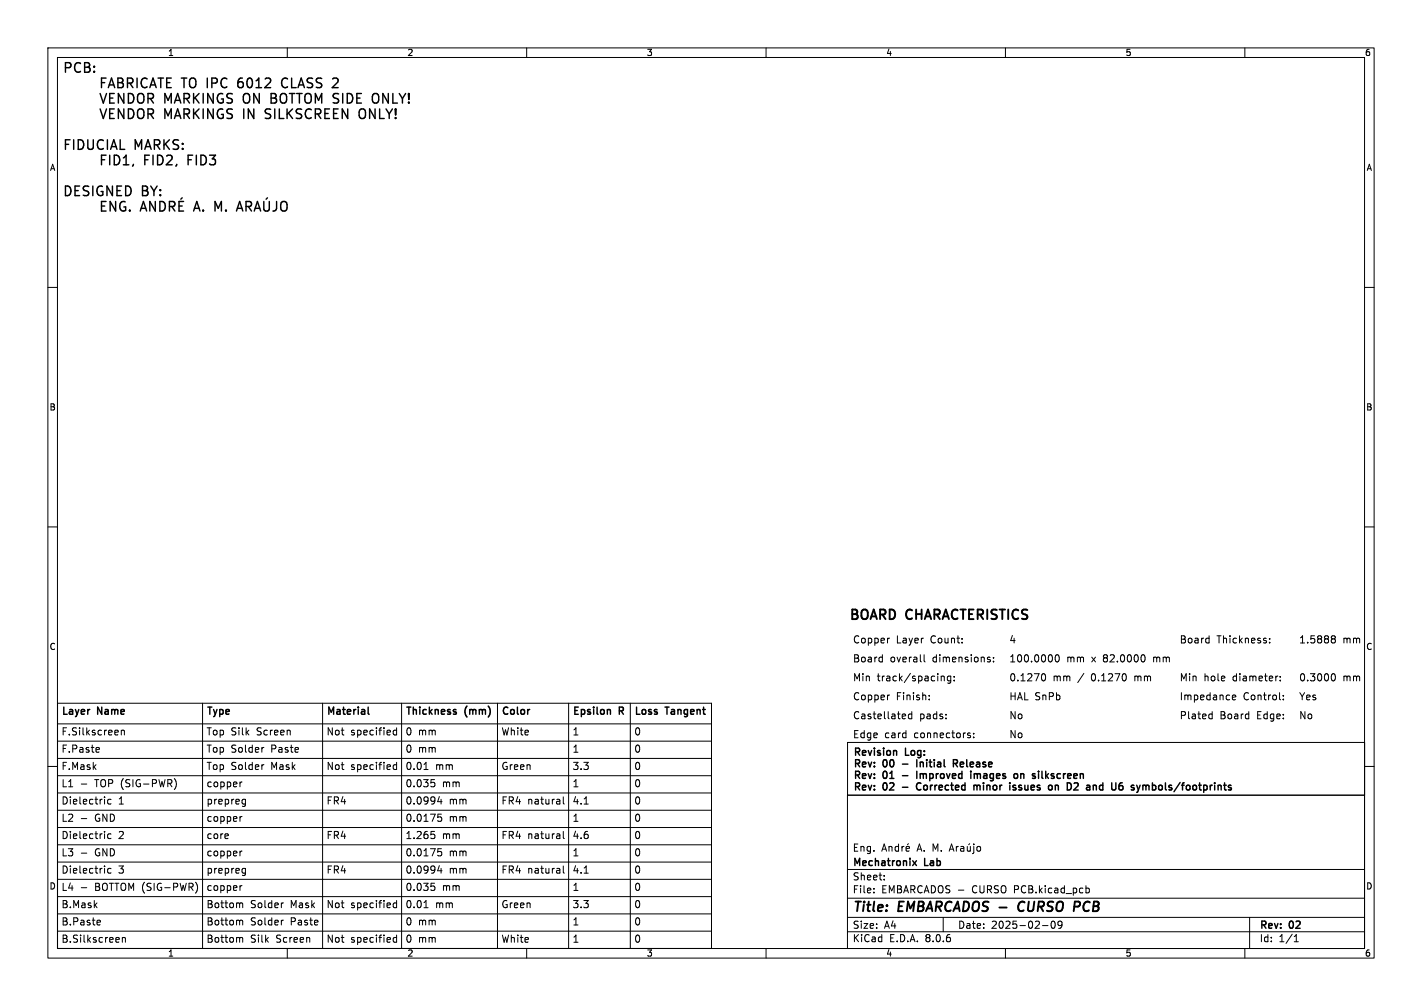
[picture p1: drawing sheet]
<svg xmlns="http://www.w3.org/2000/svg" width="297mm" height="210mm" viewBox="0 0 297 210" stroke-linecap="round" stroke-linejoin="round" font-family="sans-serif">
<defs><g id="words">
<g font-size="2.8">
<text x="13" y="15.9">PCB:</text>
<text x="13" y="19.1">FABRICATE</text>
<text x="13" y="22.3">VENDOR</text>
<text x="34.3" y="22.3">MARKINGS</text>
<text x="38" y="19.1">TO IPC</text>
<text x="50.6" y="19.1">6012</text>
<text x="51.2" y="22.3">ON</text>
<text x="57.5" y="22.3">BOTTOM SIDE</text>
<text x="60.2" y="19.1">CLASS</text>
<text x="71.4" y="19.1">2</text>
<text x="79.7" y="22.3">ONLY!</text>
<text x="13" y="25.6">VENDOR</text>
<text x="34.3" y="25.6">MARKINGS</text>
<text x="51.2" y="25.6">IN</text>
<text x="56.3" y="25.6">SILKSCREEN</text>
<text x="76.4" y="25.6">ONLY!</text>
<text x="13" y="32">FIDUCIAL</text>
<text x="28.1" y="32">MARKS:</text>
<text x="30.1" y="35.2">FID2,</text>
<text x="39.6" y="35.2">FID3</text>
<text x="13" y="41.7">DESIGNED</text>
<text x="29.6" y="41.7">BY:</text>
<text x="41" y="44.9">A.</text>
<text x="177.3" y="130.4">BOARD</text>
<text x="189.4" y="130.4">CHARACTERISTICS</text>
<text x="178" y="190.9">Title:</text>
<text x="187.7" y="190.9">EMBARCADOS -</text>
<text x="214.3" y="190.9">CURSO</text>
<text x="226.7" y="190.9">PCB</text>
</g>
<g font-size="2.1">
<text x="178" y="134.8">Copper</text>
<text x="187.2" y="134.8">Layer</text>
<text x="194.6" y="134.8">Count:</text>
<text x="210.7" y="134.8">4</text>
<text x="246.3" y="134.8">Board</text>
<text x="254.2" y="134.8">Thickness:</text>
<text x="271.2" y="134.8">1.5888</text>
<text x="280.5" y="134.8">mm</text>
<text x="178" y="142.7">Min</text>
<text x="178" y="138.7">Board</text>
<text x="183.2" y="142.7">track/spacing:</text>
<text x="186" y="138.7">overall</text>
<text x="195" y="138.7">dimensions:</text>
<text x="210.7" y="142.7">0.1270</text>
<text x="210.7" y="138.7">100.0000</text>
<text x="220" y="142.7">mm</text>
<text x="222.8" y="138.7">mm</text>
<text x="225.4" y="142.7">/</text>
<text x="228.3" y="138.7">x</text>
<text x="228.4" y="142.7">0.1270</text>
<text x="230.9" y="138.7">82.0000</text>
<text x="237.7" y="142.7">mm</text>
<text x="241.7" y="138.7">mm</text>
<text x="246.3" y="142.7">Min</text>
<text x="251.5" y="142.7">hole</text>
<text x="257.7" y="142.7">diameter:</text>
<text x="271.2" y="142.7">0.3000</text>
<text x="280.5" y="142.7">mm</text>
<text x="12.8" y="150">Layer</text>
<text x="20.4" y="150">Name</text>
<text x="43.1" y="150">Type</text>
<text x="68.1" y="150">Material</text>
<text x="84.6" y="150">Thickness</text>
<text x="97.2" y="150">(mm)</text>
<text x="104.7" y="150">Color</text>
<text x="119.5" y="150">Epsilon</text>
<text x="129.4" y="150">R</text>
<text x="132.4" y="150">Loss</text>
<text x="139.1" y="150">Tangent</text>
<text x="178" y="146.6">Copper</text>
<text x="187.2" y="146.6">Finish:</text>
<text x="210.7" y="146.6">HAL SnPb</text>
<text x="246.3" y="146.6">Impedance</text>
<text x="259.7" y="146.6">Control:</text>
<text x="271.2" y="146.6">Yes</text>
<text x="12.8" y="153.7">F.Silkscreen</text>
<text x="43.1" y="153.7">Top Silk</text>
<text x="53.3" y="153.7">Screen</text>
<text x="68.1" y="153.7">Not</text>
<text x="73.1" y="153.7">specified</text>
<text x="84.6" y="153.7">0 mm</text>
<text x="104.7" y="153.7">White</text>
<text x="119.5" y="153.7">1</text>
<text x="132.4" y="153.7">0</text>
<text x="178" y="154.5">Edge</text>
<text x="178" y="150.6">Castellated</text>
<text x="184.8" y="154.5">card</text>
<text x="191.2" y="154.5">connectors:</text>
<text x="192.1" y="150.6">pads:</text>
<text x="210.7" y="150.6">No</text>
<text x="210.7" y="154.5">No</text>
<text x="246.3" y="150.6">Plated</text>
<text x="254.8" y="150.6">Board</text>
<text x="262.8" y="150.6">Edge:</text>
<text x="271.2" y="150.6">No</text>
<text x="12.8" y="157.3">F.Paste</text>
<text x="12.8" y="160.9">F.Mask</text>
<text x="43.1" y="157.3">Top Solder</text>
<text x="43.1" y="160.9">Top Solder</text>
<text x="56.3" y="157.3">Paste</text>
<text x="56.3" y="160.9">Mask</text>
<text x="68.1" y="160.9">Not</text>
<text x="73.1" y="160.9">specified</text>
<text x="84.6" y="160.9">0.01</text>
<text x="84.6" y="157.3">0 mm</text>
<text x="90.8" y="160.9">mm</text>
<text x="104.7" y="160.9">Green</text>
<text x="119.5" y="157.3">1</text>
<text x="119.5" y="160.9">3.3</text>
<text x="132.4" y="160.9">0</text>
<text x="132.4" y="157.3">0</text>
<text x="178.1" y="158.5">Revision</text>
<text x="178.1" y="160.9">Rev:</text>
<text x="184.5" y="160.9">00</text>
<text x="189.2" y="158.5">Log:</text>
<text x="192.7" y="160.9">Initial</text>
<text x="201" y="160.9">Release</text>
<text x="12.8" y="164.5">L1</text>
<text x="19.6" y="164.5">TOP (SIG-PWR)</text>
<text x="43.1" y="164.5">copper</text>
<text x="84.6" y="164.5">0.035</text>
<text x="92.2" y="164.5">mm</text>
<text x="119.5" y="164.5">1</text>
<text x="132.4" y="164.5">0</text>
<text x="178.1" y="163.3">Rev:</text>
<text x="178.1" y="165.8">Rev:</text>
<text x="184.5" y="163.3">01</text>
<text x="184.5" y="165.8">02</text>
<text x="192.7" y="163.3">Improved</text>
<text x="192.7" y="165.8">Corrected</text>
<text x="204.6" y="163.3">images</text>
<text x="205.3" y="165.8">minor</text>
<text x="213.4" y="165.8">issues</text>
<text x="214.3" y="163.3">on</text>
<text x="218.7" y="163.3">silkscreen</text>
<text x="222.1" y="165.8">on</text>
<text x="226.6" y="165.8">D2</text>
<text x="231.2" y="165.8">and</text>
<text x="237" y="165.8">U6</text>
<text x="241.8" y="165.8">symbols/footprints</text>
<text x="12.8" y="168.1">Dielectric</text>
<text x="12.8" y="171.7">L2</text>
<text x="19.6" y="171.7">GND</text>
<text x="24.6" y="168.1">1</text>
<text x="43.1" y="168.1">prepreg</text>
<text x="43.1" y="171.7">copper</text>
<text x="68.1" y="168.1">FR4</text>
<text x="84.6" y="168.1">0.0994</text>
<text x="84.6" y="171.7">0.0175</text>
<text x="93.6" y="168.1">mm</text>
<text x="93.6" y="171.7">mm</text>
<text x="104.7" y="168.1">FR4 natural</text>
<text x="119.5" y="168.1">4.1</text>
<text x="119.5" y="171.7">1</text>
<text x="132.4" y="168.1">0</text>
<text x="132.4" y="171.7">0</text>
<text x="12.8" y="178.9">L3</text>
<text x="12.8" y="175.3">Dielectric</text>
<text x="19.6" y="178.9">GND</text>
<text x="24.6" y="175.3">2</text>
<text x="43.1" y="178.9">copper</text>
<text x="43.1" y="175.3">core</text>
<text x="68.1" y="175.3">FR4</text>
<text x="84.6" y="178.9">0.0175</text>
<text x="84.6" y="175.3">1.265</text>
<text x="92.2" y="175.3">mm</text>
<text x="93.6" y="178.9">mm</text>
<text x="104.7" y="175.3">FR4 natural</text>
<text x="119.5" y="175.3">4.6</text>
<text x="119.5" y="178.9">1</text>
<text x="132.4" y="175.3">0</text>
<text x="132.4" y="178.9">0</text>
<text x="178" y="178">Eng.</text>
<text x="191.6" y="178">A.</text>
<text x="12.8" y="182.5">Dielectric</text>
<text x="24.6" y="182.5">3</text>
<text x="43.1" y="182.5">prepreg</text>
<text x="68.1" y="182.5">FR4</text>
<text x="84.6" y="182.5">0.0994</text>
<text x="93.6" y="182.5">mm</text>
<text x="104.7" y="182.5">FR4 natural</text>
<text x="119.5" y="182.5">4.1</text>
<text x="132.4" y="182.5">0</text>
<text x="178" y="184">Sheet:</text>
<text x="178" y="181.2">Mechatronix</text>
<text x="193.2" y="181.2">Lab</text>
<text x="12.8" y="186.1">L4</text>
<text x="12.8" y="189.7">B.Mask</text>
<text x="19.6" y="186.1">BOTTOM (SIG-PWR)</text>
<text x="43.1" y="189.7">Bottom</text>
<text x="43.1" y="186.1">copper</text>
<text x="52.1" y="189.7">Solder</text>
<text x="60.4" y="189.7">Mask</text>
<text x="68.1" y="189.7">Not</text>
<text x="73.1" y="189.7">specified</text>
<text x="84.6" y="189.7">0.01</text>
<text x="84.6" y="186.1">0.035</text>
<text x="90.8" y="189.7">mm</text>
<text x="92.2" y="186.1">mm</text>
<text x="104.7" y="189.7">Green</text>
<text x="119.5" y="186.1">1</text>
<text x="119.5" y="189.7">3.3</text>
<text x="132.4" y="186.1">0</text>
<text x="132.4" y="189.7">0</text>
<text x="178" y="186.7">File:</text>
<text x="184.1" y="186.7">EMBARCADOS -</text>
<text x="203.2" y="186.7">CURSO PCB.kicad_pcb</text>
<text x="12.8" y="193.3">B.Paste</text>
<text x="12.8" y="196.9">B.Silkscreen</text>
<text x="43.1" y="196.9">Bottom</text>
<text x="43.1" y="193.3">Bottom</text>
<text x="52.1" y="196.9">Silk</text>
<text x="52.1" y="193.3">Solder</text>
<text x="57.4" y="196.9">Screen</text>
<text x="60.4" y="193.3">Paste</text>
<text x="68.1" y="196.9">Not</text>
<text x="73.1" y="196.9">specified</text>
<text x="84.6" y="196.9">0 mm</text>
<text x="84.6" y="193.3">0 mm</text>
<text x="104.7" y="196.9">White</text>
<text x="119.5" y="196.9">1</text>
<text x="119.5" y="193.3">1</text>
<text x="132.4" y="196.9">0</text>
<text x="132.4" y="193.3">0</text>
<text x="178" y="196.9">KiCad</text>
<text x="178" y="194.1">Size:</text>
<text x="184.7" y="194.1">A4</text>
<text x="185.7" y="196.9">E.D.A.</text>
<text x="193.3" y="196.9">8.0.6</text>
<text x="200" y="194.1">Date:</text>
<text x="207" y="194.1">2025-02-09</text>
<text x="263" y="194.3">Rev:</text>
<text x="263" y="196.9">Id:</text>
<text x="267.1" y="196.9">1/1</text>
<text x="269.4" y="194.3">02</text>
</g>
<g font-size="1.8">
<text x="35" y="11.9">1</text>
<text x="85" y="11.9">2</text>
<text x="135" y="11.9">3</text>
<text x="185" y="11.9">4</text>
<text x="235" y="11.9">5</text>
<text x="285" y="11.9">6</text>
<text x="10.3" y="35.9">A</text>
<text x="285.4" y="35.9">A</text>
<text x="10.3" y="85.9">B</text>
<text x="285.3" y="85.9">B</text>
<text x="10.3" y="135.9">C</text>
<text x="285.3" y="135.9">C</text>
<text x="10.3" y="185.9">D</text>
<text x="285.3" y="185.9">D</text>
<text x="35" y="199.9">1</text>
<text x="85" y="199.9">2</text>
<text x="135" y="199.9">3</text>
<text x="185" y="199.9">4</text>
<text x="235" y="199.9">5</text>
<text x="285" y="199.9">6</text>
</g>
</g></defs>
<g fill="none" stroke="#000" stroke-width=".21">
<path d="M10 10h277v190h-277zM12 12h273v186h-273zM60 10v2M110 10v2M160 10v2M210 10v2M260 10v2M10 60h2M285 60h2M10 110h2M285 110h2M184.2 137.2l.1 .1"/>
<path d="M184.3 136.7v1.5M184.3 138.1l-.1 .1M185.8 133.2l-.3 .1M193 136.7v1.3l.2 .2M206.7 137.7l.2 .2-.2 .3M206.7 137.2l.1 .1M207.5 138v.2M207.5 137.3v.1M220.5 136.8l.2-.1a.8 .8 0 0 1 .6 .7 .8 .8 0 0 1-.6 .8l-.2-.2-.1-.4zM239.1 137v.9M241 137.2v1M241.2 137.2l-.2 .1"/>
<path d="M252.4 133.2l.1 .1M252.5 132.7v1.5M252.5 134.2h-.1M265.2 134.1v.1M265.2 133.3v.1M278.2 132.8l.4-.1 .2 .2 .1 .2-.3 .3M278.2 133.3l.1 .1M278.3 133.4h.3M278.3 133.4h-.1M278.6 133.4l.3 .3-.1 .4-.2 .1h-.4M10 160h2M12 146.8h136.6v51.2h-136.6z"/>
<path d="M12 158.3h136.6M12 151.1h136.6M12 154.7h136.6M20.6 156l.2 .4-.7 .1M20.7 157h-.1M25.3 152.4v1M25.3 152.6l.3-.2 .3 .1 .1 .9M42.3 146.8v51.2M55.1 156l-.3 .2M55.1 159.6l-.3 .2M60.6 152.5v.9M62.3 156.1v.3l-.7 .1"/>
<path d="M67.4 146.8v51.2M82.8 151.9v1.5M82.8 159.1v1.5M82.8 152.5l-.4-.1-.3 .3 .2 .7h.5M82.8 159.7l-.4-.1-.3 .3 .2 .7h.5M83.9 146.8v51.2M103.9 146.8v51.2M118.8 146.8v51.2M131.6 146.8v51.2M177 155h108v11h-108zM185.8 145.1l-.3 .1M189.1 149.1l.1 .3-.8 .2"/>
<path d="M190.4 148.6v1.5M190.4 149.1h-.4l-.3 .2 .2 .7h.5M194.1 146v.1M194.1 145.2v.1M196.7 141.2h.5v.9M198.6 141.2l-.4-.1-.3 .3 .1 .7h.6M198.6 141.1v1.3l-.3 .2h-.4M199.3 142v.1M199.3 141.2v.2M202.5 153.5l.2 .2-.2 .3M202.5 153l.2 .1M203.4 153.1v.1"/>
<path d="M203.4 153.9v.1M217.7 140.8l.2-.2a.8 .8 0 0 1 .5 .8 .8 .8 0 0 1-.5 .7l-.2-.1M237 141.1v1M237.2 141.1l-.2 .2M252.8 149.1h.4M253.2 150l-.4 .1M253.2 148.6v1.5M257.4 145.6l.7-.1-.1-.3-.4-.1-.2 .2 .1 .7h.5M267.4 142v.1M267.4 141.2v.2M268 146v.1M268 145.2v.1"/>
<path d="M278.2 140.8l.2-.2a.8 .8 0 0 1 .5 .8 .8 .8 0 0 1-.5 .7l-.2-.1M285 160h2M12 172.7h136.6M12 176.4h136.6M12 169.1h136.6M12 165.5h136.6M12 180h136.6M12 161.9h136.6M17 178.1h1.1M17 170.9h1.1M17 163.7h1.1M23.2 166.9h-.4l-.3 .2 .1 .7h.6"/>
<path d="M23.2 174.1h-.4l-.3 .3 .1 .6h.6M36.4 162.5a1.72 1.72 0 0 1 0 2.3M50.6 177.7l-.5 .3M50.6 170.5l-.5 .2M50.6 163.2l-.5 .3M50.8 166.9h.5M51.3 166.9v1.2l-.2 .2-.3 .1M51.3 167.8l-.5 .1M88.5 160.6h.9M90.1 162.7h.7M90.1 173.6h.7M90.2 163.3h.3l.3 .3v.5l-.6 .1"/>
<path d="M90.2 174.1h.3l.3 .3v.5l-.6 .2M91.5 170h.7M91.5 177.2h.7M91.6 170.5h.4l.3 .3-.2 .6-.5 .1M91.6 177.7h.4l.3 .3-.2 .6-.5 .1M91.8 166.3l-.4 1.1h.9M92.1 166.9v1M117.7 166.4v1.2l.2 .3M117.7 173.6v1.3l.2 .2M122 167.9h.9M177 166h108v32h-108zM184.2 177.7l.5-1.5 .5 1.5"/>
<path d="M184.3 177.3h.7M185.7 176.7v1M185.7 176.8l.2-.1 .3 .1 .1 .9M187.7 176.8l-.5-.1-.2 .3 .1 .6h.6M187.7 176.2v1.5M188.4 176.7v1M188.8 176.7l-.4 .3M189.2 177.2l.8-.1-.1-.3-.4-.1-.3 .2 .1 .7h.6M189.7 176.1l-.2 .2M194.9 177.7v-1.5l.5 1.1 .5-1.1v1.5M196.6 177.6v.1M198.2 177.7l.5-1.5 .5 1.5"/>
<path d="M198.4 177.3h.7M199.7 176.7v1M200.2 176.7l-.5 .3M200.7 176.8h.5l.1 .9M201.3 177.1h-.5l-.2 .2 .2 .4 .5-.1M202 176.7l.1 .9 .4 .1 .2-.1M202.5 176.1l-.2 .2M202.7 176.7v1M203.4 176.2v.1M203.4 176.7v1.3l-.3 .2M204.2 176.8l.3-.1 .3 .3v.4l-.3 .3-.3-.1-.2-.2zM12 190.8h136.6"/>
<path d="M12 183.6h136.6M12 187.2h136.6M12 194.4h136.6M17 185.3h1.1M20.5 192.1l.4 .1 .1 .3-.7 .1M20.9 193l-.4 .1M23.2 181.3h-.4l-.3 .3 .1 .6h.6M25.6 195.8l.2-.1 .3 .1 .1 .9M25.6 195.7v1M40.8 184.2a1.72 1.72 0 0 1 0 2.3M50.3 188.5l.4 .2v.8M50.3 195.7l.4 .2v.8"/>
<path d="M50.3 192.1l.4 .2v.8M50.6 184.9l-.5 .3M50.8 181.3h.5M51.3 181.3v1.2l-.2 .2-.3 .1M51.3 182.2l-.5 .1M59.2 188.5l-.4 .1M59.2 192.1l-.4 .1M60 198v2M64.6 195.8l.1 .9M66.3 192.2l.1 .3-.7 .1M82.8 188v1.5M82.8 195.2v1.5"/>
<path d="M82.8 188.6l-.4-.1-.3 .3 .2 .6h.5M82.8 195.8l-.4-.1-.3 .3 .2 .6h.5M88.5 189.5h.9M90.1 184.4h.7M90.2 185h.3l.3 .2-.1 .6-.5 .1M91.8 180.7l-.4 1.1h.9M92.1 181.3v1M110 198v2M117.7 180.8v1.3l.2 .2M122 182.3h.9M160 198v2M177 194.5h108"/>
<path d="M177 191.5h108M177 187.5h108M177 181.5h108M182.5 186.3v.1M182.5 185.5v.1M184.7 183.6v.1M184.7 182.8v.1M197 191.5v3M210 198v2M217.7 193.2h1.2M219.7 192.4l.2-.1a.8 .8 0 0 1 .5 .7 .8 .8 0 0 1-.5 .8 1 1 0 0 1-.2-1.4zM221.8 192.9l-.3 .3h-.3l-.2-.3 .1-.5 .4-.1 .2 .1a.99 .99 0 0 1-.3 1.4h-.3"/>
<path d="M227 185.4l.4 .1 .1 .2v.6l-.5 .1M260 198v2M261 191.5v6.5M270.3 196.6h.9M270.3 195.5l.4-.4v1.5"/>
</g>
<g fill="none" stroke="#000" stroke-width=".4">
<path d="M179 127.4l-.3-.2h-.7v2M180 127.5a.68 .68 0 0 1 1.2 0M181.8 129.2l.7-2 .7 2M184.9 127.4l-.3-.2h-.8v2M186.8 127.5l-.5-.3h-.5v2M190.5 127.4l-.1-.1a.72 .72 0 0 0-1 .2M191.3 127.2v2M192.5 127.2v2M193.2 129.2l.6-2 .7 2M196.2 127.4l-.3-.2h-.7v2M196.9 129.2l.6-2 .7 2M200 127.4l-.1-.1a.72 .72 0 0 0-.9 .2"/>
<path d="M200.6 127.2h1.1M201.2 127.2v2M203.3 127.2h-.9v2M205.2 127.4l-.2-.2h-.8v2M206.2 127.2v2M208.2 127.3l-.8-.1-.2 .2M208.8 127.2h1.1M209.3 127.2v2M210.6 127.2v2M212.7 127.4l-.1-.1a.72 .72 0 0 0-1 .2M214.6 127.3l-.8-.1-.3 .2M213.6 188.2a1.07 1.07 0 0 0-.9 .8 1.07 1.07 0 0 0 .5 1.2l.5-.1"/>
<path d="M225.4 188.3a.53 .53 0 0 1 0 .8"/>
</g>
<g fill="none" stroke="#000" stroke-width=".3">
<path d="M24.7 19.5l1.2 2v-2M26.8 19.5v2h.5a1.06 1.06 0 0 0 .6-1.5M29.2 19.5a.67 .67 0 0 1 .9 .7v.7a.67 .67 0 0 1-.7 .6 .67 .67 0 0 1-.7-.6l.1-1.1M30.7 16.5a.8 .8 0 0 0-1 0 .8 .8 0 0 0-.2 .9 .75 .75 0 0 0 .4 .8 .75 .75 0 0 0 .8-.1M31.3 18.3l.7-2 .6 2M31.5 17.7h.9M33 16.3h1.1M33.6 16.3v2M34.8 17.3h.7M35.8 16.3h-1v2h1M49.8 16.8v1.3M49.8 17.3l-.1 .1"/>
<path d="M56.6 19.5v2h.8M59.5 16.3a1.08 1.08 0 0 0-.7 1 1.08 1.08 0 0 0 .7 1M69.8 16.3h.4l.3 .2M70.5 17.2l-1.1 1.1h1.2M78.1 19.6a.67 .67 0 0 1 .9 .2M21.2 33.4h.7M21.2 32.4v2M22.9 32.4v2M23.9 32.4v2h.4a1.06 1.06 0 0 0 .6-1.5M24.7 22.7l1.2 2v-2M25.8 34.4h1.1M26.3 32.4v2"/>
<path d="M26.8 22.7a1.01 1.01 0 0 1 1.2 1 1.01 1.01 0 0 1-1.2 1zM27.9 34.3l-.2 .4M28.8 23a.67 .67 0 0 1 .8-.3 .67 .67 0 0 1 .5 .7v.7a.67 .67 0 0 1-.7 .7 .67 .67 0 0 1-.7-.7zM30.9 20.6h.8a.54 .54 0 0 0 .4-.6 .54 .54 0 0 0-.4-.5h-.8v2M30.9 23.8h.8a.54 .54 0 0 0 .4-.5 .54 .54 0 0 0-.4-.6h-.8v2M31.4 20.6l.7 .9M31.4 23.8l.7 .9M55.4 24.6l.3 .1M55.4 23.3l.1 .2M56.6 20.5h.7M75.1 23a1.35 1.35 0 0 0 .4 1.7h.4M79 21.2a.67 .67 0 0 1-.9 .2"/>
<path d="M21.2 42.1v2h.9M21.2 43h.7M24.1 42.1v2l-1.1-2v2M25.1 42.5a.92 .92 0 0 0 0 1.1 .92 .92 0 0 0 1 .4l.1-.8h-.3M27.1 43.9v.2M29.3 44.1l.7-2 .6 2M29.5 43.5h.9M32.4 42.1v2l-1.1-2v2M33.4 42.1v2h.5a1.06 1.06 0 0 0 .5-1.6M35.4 43.1h.7a.54 .54 0 0 0 .4-.5 .54 .54 0 0 0-.4-.5h-.7v2M35.9 43.1l.6 1M37.4 43h.7"/>
<path d="M38.1 41.3l-.3 .3M38.3 42.1h-.9v2h.9M44.9 44.1v-2l.7 1.4 .6-1.4v2M47.2 43.9v.2M49.4 44.1l.7-2 .6 2M49.6 43.5h.9M51.4 43.1h.7a.54 .54 0 0 0 .4-.5 .54 .54 0 0 0-.4-.5h-.7v2M51.9 43.1l.6 1M53.1 44.1l.7-2 .6 2M53.3 43.5h.9M55.1 42.1v1.6l.4 .4 .6-.1 .1-.3v-1.6M55.9 41.3l-.3 .3"/>
<path d="M57.8 42.1v1.4a.64 .64 0 0 1-.8 .6M58.9 42.2a.66 .66 0 0 1 .7-.1 .66 .66 0 0 1 .4 .6v.7a.67 .67 0 0 1-.7 .7 .67 .67 0 0 1-.7-.7v-.7zM13.3 147.6v1.5M18.6 148.1h.2M21.3 147.6v1.5l-.9-1.5v1.5M43.4 147.6h.9M43.8 147.6v1.5M68.7 149.1v-1.5l.5 1.1 .5-1.1v1.5M71.8 147.6v1.3M74.8 147.6v.2M76.1 148.2l.1 .9M76.2 149l-.2 .1"/>
<path d="M76.2 148.5h-.2M76.9 147.6v1.3l.2 .2M85 147.6h.8M85.4 147.6v1.5M86.3 147.6v1.5M87.7 147.6v.2M89.7 147.6v1.5M94.7 148.4l.6 .4-.2 .3-.4-.1M95.3 148.2l-.4-.1-.2 .2M97.5 147.4l-.2 .4M102 147.4l.3 .4M106.1 147.8l-.5-.2-.3 .2"/>
<path d="M108.1 147.6v1.3M110.6 148.1l-.2 .1M120.8 147.6h-.7v1.5M124 147.6v.2M124.7 147.6v1.3M126.9 148.2h.5l.1 .9M130.1 147.8l-.7-.2v1.5M133 147.6v1.5M138.9 147.6h.8M139.3 147.6v1.5M147 147.6v1.3M178.7 158.6v1.5"/>
<path d="M179.5 156.3l-.8-.1v1.5M182.6 156.2v.1M184.6 156.2v.1M188.5 159.5h1.1M189.1 156.2v1.5M191.5 158.6v1.5M194.3 158.6v1.3M195.1 158.6v.1M197.2 158.6v1.3M199.1 159.4l.7-.1 .2-.2-.1-.4-.8-.1v1.5M199.5 159.4l.5 .7M201.9 158.6v1.3"/>
<path d="M178.7 161v1.5M178.7 163.4v1.5M186.3 161v1.5M188.5 161.9h1.1M188.5 164.3h1.1M190.6 179.7l.8 1M191.4 179.7l-.8 1M191.5 161v1.5M192.3 163.5a.7 .7 0 0 0-.9 .7 .7 .7 0 0 0 .9 .6M198.8 163.4v1.3M200.9 161v1.5M201.6 163.4v1.5"/>
<path d="M202.8 161.5v1M203.4 163.9v1M203.4 164.1l.2-.2 .4 .1 .1 .9M203.5 161.5v1M212.1 164.5v.3l-.4 .1M212.4 161.6l.2 .2-.2 .6M212.8 164.8l.1 .1M212.8 164v.3M213.2 161.5v1M213.6 161.5l-.4 .1M216.9 161v.1M217.6 161v1.3l.2 .2"/>
<path d="M218.4 161v1.5M221 164l.1 .9M222.9 163.4v1.5M229.8 164.8h.5M229.8 164h.5M230.3 163.4v1.5M232.2 163.4v1.2M233.1 163.4v1.2M234.4 163.4l-.5 .2M236.3 164.8l.4 .1M236.5 163.9l-.2 .2 .2 .3M240.7 164.8l.4 .1"/>
<path d="M240.7 163.4v1.5M241.1 163.9l-.4 .1M243.4 163.4v1.3M246.5 163.3l-1.3 2M247.3 163.4l-.3 .2M250.6 163.4v1.3M253.7 163.4v.2M255.8 163.4v1.3"/>
</g>
<use href="#words"/>
</svg>
